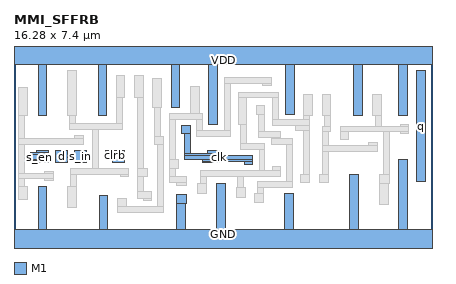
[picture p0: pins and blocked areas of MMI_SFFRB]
MACRO MMI_SFFRB
	CLASS CORE ;
	FOREIGN MMI_SFFRB 0 0 ;
	SIZE 16.28 BY 7.4 ;
	SYMMETRY X Y ;
	SITE CORE1 ;
	PIN d
		DIRECTION input ;
		USE SIGNAL ;
		PORT
			LAYER M1 ;
			RECT 1.625 3.105 2.075 3.555 ;
		END
		AntennaGateArea 0.4968 ;
	END d
	PIN GND
		DIRECTION inout ;
		USE GROUND ;
		PORT
			LAYER M1 ;
			RECT 0.94 0.5 1.28 2.175 ;
			LAYER M1 ;
			RECT 3.32 0.5 3.66 1.795 ;
			LAYER M1 ;
			RECT 6.32 1.5 6.7 1.84 ;
			LAYER M1 ;
			RECT 6.335 0.5 6.675 1.5 ;
			LAYER M1 ;
			RECT 7.88 0.5 8.22 2.28 ;
			LAYER M1 ;
			RECT 10.53 0.5 10.87 1.875 ;
			LAYER M1 ;
			RECT 13.085 0.5 13.425 2.64 ;
			LAYER M1 ;
			RECT 14.97 0.5 15.31 3.205 ;
			LAYER M1 ;
			RECT 0 -0.5 16.28 0.5 ;
		END
	END GND
	PIN q
		DIRECTION output ;
		USE SIGNAL ;
		PORT
			LAYER M1 ;
			RECT 15.69 2.365 16.03 6.67 ;
		END
		AntennaDiffArea 1.3248 ;
	END q
	PIN s_en
		DIRECTION input ;
		USE SIGNAL ;
		PORT
			LAYER M1 ;
			RECT 0.885 3.5 1.335 3.555 ;
			LAYER M1 ;
			RECT 0.66 3.425 1.335 3.5 ;
			LAYER M1 ;
			RECT 0.645 3.195 1.335 3.425 ;
			LAYER M1 ;
			RECT 0.66 3.16 1.335 3.195 ;
			LAYER M1 ;
			RECT 0.885 3.105 1.335 3.16 ;
		END
		AntennaGateArea 0.738 ;
	END s_en
	PIN s_in
		DIRECTION input ;
		USE SIGNAL ;
		PORT
			LAYER M1 ;
			RECT 2.365 3.105 2.815 3.555 ;
		END
		AntennaGateArea 0.2484 ;
	END s_in
	PIN VDD
		DIRECTION inout ;
		USE POWER ;
		PORT
			LAYER M1 ;
			RECT 0 6.9 16.28 7.9 ;
			LAYER M1 ;
			RECT 0.94 4.91 1.28 6.9 ;
			LAYER M1 ;
			RECT 3.28 4.91 3.62 6.9 ;
			LAYER M1 ;
			RECT 6.12 5.24 6.46 6.9 ;
			LAYER M1 ;
			RECT 7.58 4.56 7.92 6.9 ;
			LAYER M1 ;
			RECT 10.58 4.985 10.92 6.9 ;
			LAYER M1 ;
			RECT 13.235 4.91 13.575 6.9 ;
			LAYER M1 ;
			RECT 14.97 4.91 15.31 6.9 ;
		END
	END VDD
	PIN clk
		DIRECTION input ;
		USE CLOCK ;
		PORT
			LAYER M1 ;
			RECT 6.52 4.21 6.86 4.55 ;
			LAYER M1 ;
			RECT 6.63 3.43 6.86 4.21 ;
			LAYER M1 ;
			RECT 7.545 3.445 7.995 3.555 ;
			LAYER M1 ;
			RECT 7.34 3.43 7.995 3.445 ;
			LAYER M1 ;
			RECT 6.63 3.375 7.995 3.43 ;
			LAYER M1 ;
			RECT 6.63 3.2 9.3 3.375 ;
			LAYER M1 ;
			RECT 7.34 3.145 9.3 3.2 ;
			LAYER M1 ;
			RECT 7.34 3.105 7.995 3.145 ;
			LAYER M1 ;
			RECT 8.96 3.035 9.3 3.145 ;
		END
		AntennaGateArea 0.6408 ;
	END clk
	PIN clrb
		DIRECTION input ;
		USE SIGNAL ;
		PORT
			LAYER M1 ;
			RECT 3.56 3.555 3.9 3.56 ;
			LAYER M1 ;
			RECT 3.56 3.22 4.295 3.555 ;
			LAYER M1 ;
			RECT 3.845 3.105 4.295 3.22 ;
		END
		AntennaGateArea 0.7128 ;
	END clrb
	OBS
		LAYER M1 ;
		RECT 0.18 4.91 0.52 6.03 ;
		LAYER M1 ;
		RECT 2.09 4.91 2.43 6.67 ;
		LAYER M1 ;
		RECT 3.98 5.635 4.32 6.475 ;
		LAYER M1 ;
		RECT 4.7 5.635 5.04 6.475 ;
		LAYER M1 ;
		RECT 0.18 4.015 0.41 4.91 ;
		LAYER M1 ;
		RECT 2.15 4.625 2.38 4.91 ;
		LAYER M1 ;
		RECT 3.98 4.625 4.21 5.635 ;
		LAYER M1 ;
		RECT 2.15 4.395 4.21 4.625 ;
		LAYER M1 ;
		RECT 2.37 4.015 2.71 4.165 ;
		LAYER M1 ;
		RECT 0.18 3.785 2.71 4.015 ;
		LAYER M1 ;
		RECT 0.18 2.685 0.41 3.785 ;
		LAYER M1 ;
		RECT 3.05 2.875 3.28 4.395 ;
		LAYER M1 ;
		RECT 4.81 2.875 5.04 5.635 ;
		LAYER M1 ;
		RECT 5.4 5.24 5.74 6.36 ;
		LAYER M1 ;
		RECT 5.49 4.12 5.72 5.24 ;
		LAYER M1 ;
		RECT 6.88 5.01 7.22 6.075 ;
		LAYER M1 ;
		RECT 6.06 4.78 7.35 5.01 ;
		LAYER M1 ;
		RECT 5.49 3.78 5.83 4.12 ;
		LAYER M1 ;
		RECT 1.18 2.685 1.52 2.745 ;
		LAYER M1 ;
		RECT 0.18 2.455 1.52 2.685 ;
		LAYER M1 ;
		RECT 0.18 2.175 0.41 2.455 ;
		LAYER M1 ;
		RECT 1.18 2.405 1.52 2.455 ;
		LAYER M1 ;
		RECT 2.2 2.645 4.47 2.875 ;
		LAYER M1 ;
		RECT 2.2 2.175 2.43 2.645 ;
		LAYER M1 ;
		RECT 4.13 2.535 4.47 2.645 ;
		LAYER M1 ;
		RECT 4.81 2.535 5.19 2.875 ;
		LAYER M1 ;
		RECT 0.18 1.655 0.52 2.175 ;
		LAYER M1 ;
		RECT 2.09 1.335 2.43 2.175 ;
		LAYER M1 ;
		RECT 4.81 1.955 5.04 2.535 ;
		LAYER M1 ;
		RECT 4.81 1.71 5.37 1.955 ;
		LAYER M1 ;
		RECT 4.04 1.38 4.38 1.71 ;
		LAYER M1 ;
		RECT 5.03 1.615 5.37 1.71 ;
		LAYER M1 ;
		RECT 5.6 1.38 5.83 3.78 ;
		LAYER M1 ;
		RECT 6.06 3.215 6.29 4.78 ;
		LAYER M1 ;
		RECT 7.12 4.325 7.35 4.78 ;
		LAYER M1 ;
		RECT 8.21 6.19 10.01 6.42 ;
		LAYER M1 ;
		RECT 8.21 4.325 8.44 6.19 ;
		LAYER M1 ;
		RECT 9.67 6.08 10.01 6.19 ;
		LAYER M1 ;
		RECT 8.73 5.61 10.305 5.84 ;
		LAYER M1 ;
		RECT 8.73 4.56 9.07 5.61 ;
		LAYER M1 ;
		RECT 9.43 4.985 9.77 5.325 ;
		LAYER M1 ;
		RECT 7.12 4.095 8.44 4.325 ;
		LAYER M1 ;
		RECT 8.84 3.835 9.07 4.56 ;
		LAYER M1 ;
		RECT 9.54 4.295 9.77 4.985 ;
		LAYER M1 ;
		RECT 10.075 4.755 10.305 5.61 ;
		LAYER M1 ;
		RECT 11.28 4.91 11.62 5.75 ;
		LAYER M1 ;
		RECT 12 4.91 12.34 5.75 ;
		LAYER M1 ;
		RECT 13.955 4.91 14.295 5.75 ;
		LAYER M1 ;
		RECT 11.28 4.755 11.51 4.91 ;
		LAYER M1 ;
		RECT 10.075 4.525 11.51 4.755 ;
		LAYER M1 ;
		RECT 10.945 4.34 11.51 4.525 ;
		LAYER M1 ;
		RECT 12.11 4.515 12.34 4.91 ;
		LAYER M1 ;
		RECT 14.065 4.515 14.295 4.91 ;
		LAYER M1 ;
		RECT 15.04 4.515 15.38 4.58 ;
		LAYER M1 ;
		RECT 9.54 4.065 10.375 4.295 ;
		LAYER M1 ;
		RECT 10.035 4.015 10.375 4.065 ;
		LAYER M1 ;
		RECT 8.84 3.605 9.775 3.835 ;
		LAYER M1 ;
		RECT 10.035 3.785 10.855 4.015 ;
		LAYER M1 ;
		RECT 6.06 2.875 6.4 3.215 ;
		LAYER M1 ;
		RECT 6.06 2.56 6.29 2.875 ;
		LAYER M1 ;
		RECT 9.545 2.8 9.775 3.605 ;
		LAYER M1 ;
		RECT 10.05 2.8 10.39 2.945 ;
		LAYER M1 ;
		RECT 7.27 2.57 10.39 2.8 ;
		LAYER M1 ;
		RECT 6.06 2.33 6.7 2.56 ;
		LAYER M1 ;
		RECT 6.32 2.22 6.7 2.33 ;
		LAYER M1 ;
		RECT 7.27 2.28 7.5 2.57 ;
		LAYER M1 ;
		RECT 7.16 1.9 7.5 2.28 ;
		LAYER M1 ;
		RECT 4.04 1.15 5.83 1.38 ;
		LAYER M1 ;
		RECT 8.71 2.11 8.94 2.57 ;
		LAYER M1 ;
		RECT 10.625 2.34 10.855 3.785 ;
		LAYER M1 ;
		RECT 11.28 2.64 11.51 4.34 ;
		LAYER M1 ;
		RECT 12 4.285 12.34 4.515 ;
		LAYER M1 ;
		RECT 12.705 4.285 15.38 4.515 ;
		LAYER M1 ;
		RECT 12 3.745 12.23 4.285 ;
		LAYER M1 ;
		RECT 12.705 3.985 13.045 4.285 ;
		LAYER M1 ;
		RECT 13.815 3.745 14.155 3.87 ;
		LAYER M1 ;
		RECT 12 3.515 14.155 3.745 ;
		LAYER M1 ;
		RECT 12 2.64 12.23 3.515 ;
		LAYER M1 ;
		RECT 14.395 2.64 14.625 4.285 ;
		LAYER M1 ;
		RECT 15.04 4.24 15.38 4.285 ;
		LAYER M1 ;
		RECT 9.49 2.11 10.855 2.34 ;
		LAYER M1 ;
		RECT 11.17 2.3 11.51 2.64 ;
		LAYER M1 ;
		RECT 11.89 2.3 12.23 2.64 ;
		LAYER M1 ;
		RECT 8.68 1.73 9.02 2.11 ;
		LAYER M1 ;
		RECT 9.49 1.875 9.72 2.11 ;
		LAYER M1 ;
		RECT 9.38 1.535 9.72 1.875 ;
		LAYER M1 ;
		RECT 14.235 2.26 14.625 2.64 ;
		LAYER M1 ;
		RECT 14.235 1.48 14.575 2.26 ;
	END
END MMI_SFFRB
